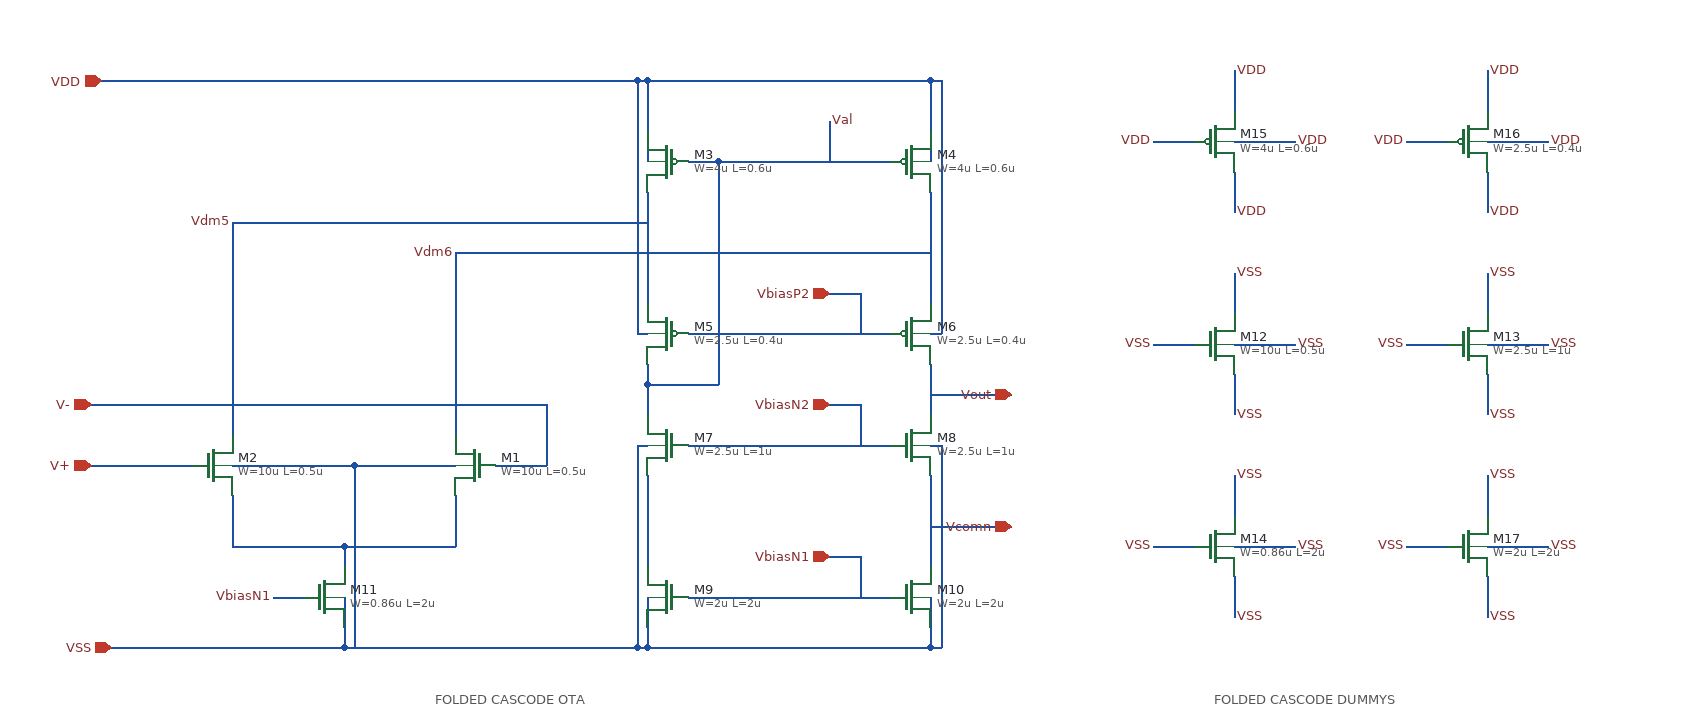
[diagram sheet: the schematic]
v {xschem version=3.4.7 file_version=1.2}
G {}
K {}
V {}
S {}
E {}
T {FOLDED CASCODE OTA} 400 -30 0 0 0.4 0.4 {}
T {FOLDED CASCODE DUMMYS} 1170 -30 0 0 0.4 0.4 {}
N 610 -500 610 -410 {
lab=Vdm5}
N 890 -470 890 -410 {
lab=Vdm6}
N 610 -240 610 -150 {
lab=#net1}
N 890 -240 890 -150 {
lab=Vcomn}
N 890 -350 890 -300 {
lab=Vout}
N 610 -330 610 -300 {
lab=Val}
N 800 -380 850 -380 {
lab=VbiasP2}
N 800 -550 850 -550 {
lab=Val}
N 680 -550 680 -330 {
lab=Val}
N 800 -270 850 -270 {
lab=VbiasN2}
N 800 -120 850 -120 {
lab=VbiasN1}
N 610 -630 610 -550 {
lab=VDD}
N 800 -630 890 -630 {
lab=VDD}
N 890 -630 890 -550 {
lab=VDD}
N 230 -490 610 -490 {
lab=Vdm5}
N 800 -70 890 -70 {
lab=VSS}
N 820 -420 820 -380 {
lab=VbiasP2}
N 890 -120 890 -70 {
lab=VSS}
N 610 -120 610 -70 {
lab=VSS}
N 600 -270 610 -270 {
lab=VSS}
N 600 -270 600 -70 {
lab=VSS}
N 890 -270 900 -270 {
lab=VSS}
N 900 -270 900 -70 {
lab=VSS}
N 890 -70 900 -70 {
lab=VSS}
N 600 -380 610 -380 {
lab=VDD}
N 600 -630 600 -380 {
lab=VDD}
N 600 -630 610 -630 {
lab=VDD}
N 890 -630 900 -630 {
lab=VDD}
N 900 -630 900 -380 {
lab=VDD}
N 890 -380 900 -380 {
lab=VDD}
N 820 -310 820 -270 {
lab=VbiasN2}
N 820 -160 820 -120 {
lab=VbiasN1}
N 310 -70 600 -70 {
lab=VSS}
N 600 -70 610 -70 {
lab=VSS}
N 790 -590 790 -550 {lab=Val}
N 610 -350 610 -330 {
lab=Val}
N 650 -550 680 -550 {
lab=Val}
N 610 -520 610 -500 {
lab=Vdm5}
N 890 -520 890 -470 {
lab=Vdm6}
N 650 -380 700 -380 {
lab=VbiasP2}
N 610 -630 700 -630 {
lab=VDD}
N 650 -270 700 -270 {
lab=VbiasN2}
N 650 -120 700 -120 {
lab=VbiasN1}
N 610 -70 700 -70 {
lab=VSS}
N 680 -550 700 -550 {
lab=Val}
N 1190 -640 1190 -600 {lab=VDD}
N 1190 -540 1190 -500 {lab=VDD}
N 1190 -570 1250 -570 {lab=VDD}
N 1110 -570 1150 -570 {lab=VDD}
N 1440 -640 1440 -600 {lab=VDD}
N 1440 -540 1440 -500 {lab=VDD}
N 1440 -570 1500 -570 {lab=VDD}
N 1360 -570 1400 -570 {lab=VDD}
N 1440 -440 1440 -400 {lab=VSS}
N 1440 -340 1440 -300 {lab=VSS}
N 1440 -370 1500 -370 {lab=VSS}
N 1360 -370 1400 -370 {lab=VSS}
N 1190 -440 1190 -400 {lab=VSS}
N 1190 -340 1190 -300 {lab=VSS}
N 1190 -370 1250 -370 {lab=VSS}
N 1110 -370 1150 -370 {lab=VSS}
N 1190 -240 1190 -200 {lab=VSS}
N 1190 -140 1190 -100 {lab=VSS}
N 1190 -170 1250 -170 {lab=VSS}
N 1110 -170 1150 -170 {lab=VSS}
N 130 -250 160 -250 {
lab=V+}
N 460 -250 490 -250 {
lab=#net2}
N 200 -220 200 -170 {
lab=#net3}
N 420 -220 420 -170 {
lab=#net3}
N 310 -170 310 -150 {
lab=#net3}
N 240 -120 270 -120 {
lab=VbiasN1}
N 310 -120 310 -70 {
lab=VSS}
N 320 -250 390 -250 {lab=VSS}
N 230 -170 310 -170 {
lab=#net3}
N 230 -250 310 -250 {lab=VSS}
N 310 -170 390 -170 {lab=#net3}
N 310 -250 320 -250 {lab=VSS}
N 490 -460 890 -460 {lab=Vdm6}
N 420 -460 420 -280 {lab=Vdm6}
N 200 -490 200 -280 {lab=Vdm5}
N 1440 -240 1440 -200 {lab=VSS}
N 1440 -140 1440 -100 {lab=VSS}
N 1440 -170 1500 -170 {lab=VSS}
N 1360 -170 1400 -170 {lab=VSS}
N 890 -320 970 -320 {lab=Vout}
N 700 -120 800 -120 {lab=VbiasN1}
N 700 -70 800 -70 {lab=VSS}
N 700 -270 800 -270 {lab=VbiasN2}
N 700 -380 800 -380 {lab=VbiasP2}
N 700 -550 800 -550 {lab=Val}
N 700 -630 800 -630 {lab=VDD}
N 790 -420 820 -420 {lab=VbiasP2}
N 790 -310 820 -310 {lab=VbiasN2}
N 790 -160 820 -160 {lab=VbiasN1}
N 890 -190 970 -190 {lab=Vcomn}
N 70 -630 600 -630 {lab=VDD}
N 80 -70 310 -70 {lab=VSS}
N 610 -330 670 -330 {lab=Val}
N 670 -330 680 -330 {lab=Val}
N 90 -310 510 -310 {lab=V-}
N 510 -310 510 -250 {lab=#net2}
N 490 -250 510 -250 {lab=#net2}
N 390 -250 410 -250 {lab=VSS}
N 410 -250 420 -250 {lab=VSS}
N 390 -170 420 -170 {lab=#net3}
N 60 -250 130 -250 {lab=V+}
N 200 -250 230 -250 {lab=VSS}
N 200 -170 230 -170 {lab=#net3}
N 320 -250 320 -70 {lab=VSS}
N 60 -310 90 -310 {lab=V-}
N 420 -460 490 -460 {lab=Vdm6}
N 200 -490 230 -490 {lab=Vdm5}
C {devices/ipin.sym} 790 -310 0 0 {name=p45 lab=VbiasN2}
C {devices/iopin.sym} 70 -630 2 0 {name=p46 lab=VDD}
C {devices/ipin.sym} 790 -420 0 0 {name=p14 lab=VbiasP2}
C {devices/ipin.sym} 790 -160 0 0 {name=p9 lab=VbiasN1}
C {devices/ipin.sym} 60 -250 0 0 {name=p22 lab=V+}
C {devices/ipin.sym} 60 -310 0 0 {name=p15 lab=V-}
C {devices/iopin.sym} 80 -70 2 0 {name=p2 lab=VSS}
C {devices/lab_wire.sym} 790 -590 0 1 {name=p17 sig_type=std_logic lab=Val}
C {symbols/pfet_03v3.sym} 870 -550 0 0 {name=M4
L=0.6u
W=4u
nf=1
m=10
ad="'int((nf+1)/2) * W/nf * 0.18u'"
pd="'2*int((nf+1)/2) * (W/nf + 0.18u)'"
as="'int((nf+2)/2) * W/nf * 0.18u'"
ps="'2*int((nf+2)/2) * (W/nf + 0.18u)'"
nrd="'0.18u / W'" nrs="'0.18u / W'"
sa=0 sb=0 sd=0
model=pfet_03v3
spiceprefix=X
}
C {symbols/pfet_03v3.sym} 630 -550 0 1 {name=M3
L=0.6u
W=4u
nf=1
m=10
ad="'int((nf+1)/2) * W/nf * 0.18u'"
pd="'2*int((nf+1)/2) * (W/nf + 0.18u)'"
as="'int((nf+2)/2) * W/nf * 0.18u'"
ps="'2*int((nf+2)/2) * (W/nf + 0.18u)'"
nrd="'0.18u / W'" nrs="'0.18u / W'"
sa=0 sb=0 sd=0
model=pfet_03v3
spiceprefix=X
}
C {symbols/pfet_03v3.sym} 630 -380 0 1 {name=M5
L=0.4u
W=2.5u
nf=1
m=4
ad="'int((nf+1)/2) * W/nf * 0.18u'"
pd="'2*int((nf+1)/2) * (W/nf + 0.18u)'"
as="'int((nf+2)/2) * W/nf * 0.18u'"
ps="'2*int((nf+2)/2) * (W/nf + 0.18u)'"
nrd="'0.18u / W'" nrs="'0.18u / W'"
sa=0 sb=0 sd=0
model=pfet_03v3
spiceprefix=X
}
C {symbols/pfet_03v3.sym} 870 -380 0 0 {name=M6
L=0.4u
W=2.5u
nf=1
m=4
ad="'int((nf+1)/2) * W/nf * 0.18u'"
pd="'2*int((nf+1)/2) * (W/nf + 0.18u)'"
as="'int((nf+2)/2) * W/nf * 0.18u'"
ps="'2*int((nf+2)/2) * (W/nf + 0.18u)'"
nrd="'0.18u / W'" nrs="'0.18u / W'"
sa=0 sb=0 sd=0
model=pfet_03v3
spiceprefix=X
}
C {symbols/nfet_03v3.sym} 630 -120 0 1 {name=M9
L=2u
W=2u
nf=1
m=3
ad="'int((nf+1)/2) * W/nf * 0.18u'"
pd="'2*int((nf+1)/2) * (W/nf + 0.18u)'"
as="'int((nf+2)/2) * W/nf * 0.18u'"
ps="'2*int((nf+2)/2) * (W/nf + 0.18u)'"
nrd="'0.18u / W'" nrs="'0.18u / W'"
sa=0 sb=0 sd=0
model=nfet_03v3
spiceprefix=X
}
C {symbols/nfet_03v3.sym} 870 -270 0 0 {name=M8
L=1u
W=2.5u
nf=1
m=2
ad="'int((nf+1)/2) * W/nf * 0.18u'"
pd="'2*int((nf+1)/2) * (W/nf + 0.18u)'"
as="'int((nf+2)/2) * W/nf * 0.18u'"
ps="'2*int((nf+2)/2) * (W/nf + 0.18u)'"
nrd="'0.18u / W'" nrs="'0.18u / W'"
sa=0 sb=0 sd=0
model=nfet_03v3
spiceprefix=X
}
C {symbols/nfet_03v3.sym} 630 -270 0 1 {name=M7
L=1u
W=2.5u
nf=1
m=2
ad="'int((nf+1)/2) * W/nf * 0.18u'"
pd="'2*int((nf+1)/2) * (W/nf + 0.18u)'"
as="'int((nf+2)/2) * W/nf * 0.18u'"
ps="'2*int((nf+2)/2) * (W/nf + 0.18u)'"
nrd="'0.18u / W'" nrs="'0.18u / W'"
sa=0 sb=0 sd=0
model=nfet_03v3
spiceprefix=X
}
C {symbols/nfet_03v3.sym} 870 -120 0 0 {name=M10
L=2u
W=2u
nf=1
m=3
ad="'int((nf+1)/2) * W/nf * 0.18u'"
pd="'2*int((nf+1)/2) * (W/nf + 0.18u)'"
as="'int((nf+2)/2) * W/nf * 0.18u'"
ps="'2*int((nf+2)/2) * (W/nf + 0.18u)'"
nrd="'0.18u / W'" nrs="'0.18u / W'"
sa=0 sb=0 sd=0
model=nfet_03v3
spiceprefix=X
}
C {symbols/pfet_03v3.sym} 1170 -570 0 0 {name=M15
L=0.6u
W=4u
nf=1
m=28
ad="'int((nf+1)/2) * W/nf * 0.18u'"
pd="'2*int((nf+1)/2) * (W/nf + 0.18u)'"
as="'int((nf+2)/2) * W/nf * 0.18u'"
ps="'2*int((nf+2)/2) * (W/nf + 0.18u)'"
nrd="'0.18u / W'" nrs="'0.18u / W'"
sa=0 sb=0 sd=0
model=pfet_03v3
spiceprefix=X
}
C {devices/lab_wire.sym} 1190 -640 0 1 {name=p11 sig_type=std_logic lab=VDD
}
C {devices/lab_wire.sym} 1250 -570 0 1 {name=p31 sig_type=std_logic lab=VDD
}
C {devices/lab_wire.sym} 1110 -570 0 0 {name=p32 sig_type=std_logic lab=VDD
}
C {devices/lab_wire.sym} 1190 -500 0 1 {name=p47 sig_type=std_logic lab=VDD
}
C {symbols/pfet_03v3.sym} 1420 -570 0 0 {name=M16
L=0.4u
W=2.5u
nf=1
m=16
ad="'int((nf+1)/2) * W/nf * 0.18u'"
pd="'2*int((nf+1)/2) * (W/nf + 0.18u)'"
as="'int((nf+2)/2) * W/nf * 0.18u'"
ps="'2*int((nf+2)/2) * (W/nf + 0.18u)'"
nrd="'0.18u / W'" nrs="'0.18u / W'"
sa=0 sb=0 sd=0
model=pfet_03v3
spiceprefix=X
}
C {devices/lab_wire.sym} 1440 -640 0 1 {name=p36 sig_type=std_logic lab=VDD
L=1.5u
m=20}
C {devices/lab_wire.sym} 1500 -570 0 1 {name=p37 sig_type=std_logic lab=VDD
}
C {devices/lab_wire.sym} 1360 -570 0 0 {name=p38 sig_type=std_logic lab=VDD}
C {devices/lab_wire.sym} 1440 -500 0 1 {name=p39 sig_type=std_logic lab=VDD}
C {devices/lab_wire.sym} 1440 -440 0 1 {name=p40 sig_type=std_logic lab=VSS}
C {devices/lab_wire.sym} 1500 -370 0 1 {name=p41 sig_type=std_logic lab=VSS}
C {devices/lab_wire.sym} 1360 -370 0 0 {name=p42 sig_type=std_logic lab=VSS}
C {devices/lab_wire.sym} 1440 -300 0 1 {name=p43 sig_type=std_logic lab=VSS}
C {symbols/nfet_03v3.sym} 1420 -370 0 0 {name=M13
L=1u
W=2.5u
nf=1
m=12
ad="'int((nf+1)/2) * W/nf * 0.18u'"
pd="'2*int((nf+1)/2) * (W/nf + 0.18u)'"
as="'int((nf+2)/2) * W/nf * 0.18u'"
ps="'2*int((nf+2)/2) * (W/nf + 0.18u)'"
nrd="'0.18u / W'" nrs="'0.18u / W'"
sa=0 sb=0 sd=0
model=nfet_03v3
spiceprefix=X
}
C {devices/lab_wire.sym} 1190 -440 0 1 {name=p18 sig_type=std_logic lab=VSS}
C {devices/lab_wire.sym} 1250 -370 0 1 {name=p19 sig_type=std_logic lab=VSS}
C {devices/lab_wire.sym} 1110 -370 0 0 {name=p20 sig_type=std_logic lab=VSS}
C {devices/lab_wire.sym} 1190 -300 0 1 {name=p25 sig_type=std_logic lab=VSS}
C {symbols/nfet_03v3.sym} 1170 -370 0 0 {name=M12
L=0.5u
W=10u
nf=1
m=38
ad="'int((nf+1)/2) * W/nf * 0.18u'"
pd="'2*int((nf+1)/2) * (W/nf + 0.18u)'"
as="'int((nf+2)/2) * W/nf * 0.18u'"
ps="'2*int((nf+2)/2) * (W/nf + 0.18u)'"
nrd="'0.18u / W'" nrs="'0.18u / W'"
sa=0 sb=0 sd=0
model=nfet_03v3
spiceprefix=X
}
C {devices/lab_wire.sym} 1190 -240 0 1 {name=p26 sig_type=std_logic lab=VSS}
C {devices/lab_wire.sym} 1250 -170 0 1 {name=p27 sig_type=std_logic lab=VSS}
C {devices/lab_wire.sym} 1110 -170 0 0 {name=p28 sig_type=std_logic lab=VSS}
C {devices/lab_wire.sym} 1190 -100 0 1 {name=p29 sig_type=std_logic lab=VSS}
C {symbols/nfet_03v3.sym} 1170 -170 0 0 {name=M14
L=2u
W=0.86u
nf=1
m=46
ad="'int((nf+1)/2) * W/nf * 0.18u'"
pd="'2*int((nf+1)/2) * (W/nf + 0.18u)'"
as="'int((nf+2)/2) * W/nf * 0.18u'"
ps="'2*int((nf+2)/2) * (W/nf + 0.18u)'"
nrd="'0.18u / W'" nrs="'0.18u / W'"
sa=0 sb=0 sd=0
model=nfet_03v3
spiceprefix=X
}
C {devices/iopin.sym} 970 -190 0 0 {name=p23 lab=Vcomn}
C {devices/iopin.sym} 970 -320 0 0 {name=p21 lab=Vout}
C {devices/lab_wire.sym} 200 -490 0 0 {name=p30 sig_type=std_logic lab=Vdm5}
C {devices/lab_wire.sym} 240 -120 0 0 {name=p48 sig_type=std_logic lab=VbiasN1}
C {devices/lab_wire.sym} 420 -460 0 0 {name=p49 sig_type=std_logic lab=Vdm6}
C {symbols/nfet_03v3.sym} 440 -250 0 1 {name=M1
L=0.5u
W=10u
nf=1
m=15
ad="'int((nf+1)/2) * W/nf * 0.18u'"
pd="'2*int((nf+1)/2) * (W/nf + 0.18u)'"
as="'int((nf+2)/2) * W/nf * 0.18u'"
ps="'2*int((nf+2)/2) * (W/nf + 0.18u)'"
nrd="'0.18u / W'" nrs="'0.18u / W'"
sa=0 sb=0 sd=0
model=nfet_03v3
spiceprefix=X
}
C {symbols/nfet_03v3.sym} 180 -250 0 0 {name=M2
L=0.5u
W=10u
nf=1
m=15
ad="'int((nf+1)/2) * W/nf * 0.18u'"
pd="'2*int((nf+1)/2) * (W/nf + 0.18u)'"
as="'int((nf+2)/2) * W/nf * 0.18u'"
ps="'2*int((nf+2)/2) * (W/nf + 0.18u)'"
nrd="'0.18u / W'" nrs="'0.18u / W'"
sa=0 sb=0 sd=0
model=nfet_03v3
spiceprefix=X
}
C {symbols/nfet_03v3.sym} 290 -120 0 0 {name=M11
L=2u
W=0.86u
nf=1
m=98
ad="'int((nf+1)/2) * W/nf * 0.18u'"
pd="'2*int((nf+1)/2) * (W/nf + 0.18u)'"
as="'int((nf+2)/2) * W/nf * 0.18u'"
ps="'2*int((nf+2)/2) * (W/nf + 0.18u)'"
nrd="'0.18u / W'" nrs="'0.18u / W'"
sa=0 sb=0 sd=0
model=nfet_03v3
spiceprefix=X
}
C {devices/lab_wire.sym} 1440 -240 0 1 {name=p6 sig_type=std_logic lab=VSS}
C {devices/lab_wire.sym} 1500 -170 0 1 {name=p7 sig_type=std_logic lab=VSS}
C {devices/lab_wire.sym} 1360 -170 0 0 {name=p10 sig_type=std_logic lab=VSS}
C {devices/lab_wire.sym} 1440 -100 0 1 {name=p12 sig_type=std_logic lab=VSS}
C {symbols/nfet_03v3.sym} 1420 -170 0 0 {name=M17
L=2u
W=2u
nf=1
m=14
ad="'int((nf+1)/2) * W/nf * 0.18u'"
pd="'2*int((nf+1)/2) * (W/nf + 0.18u)'"
as="'int((nf+2)/2) * W/nf * 0.18u'"
ps="'2*int((nf+2)/2) * (W/nf + 0.18u)'"
nrd="'0.18u / W'" nrs="'0.18u / W'"
sa=0 sb=0 sd=0
model=nfet_03v3
spiceprefix=X
}
